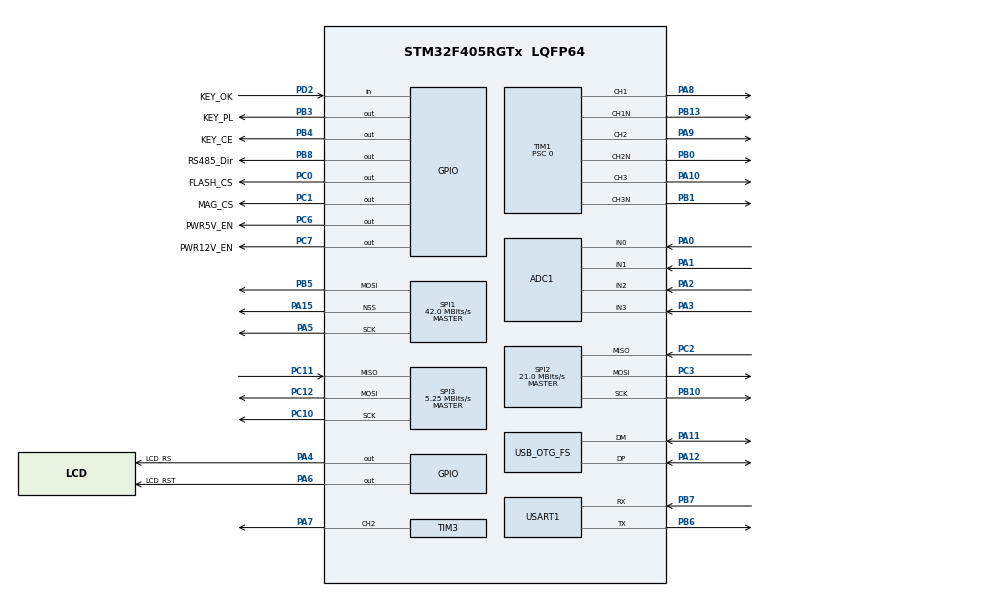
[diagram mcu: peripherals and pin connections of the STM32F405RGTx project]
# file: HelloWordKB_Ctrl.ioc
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ADC1.Channel-0\#ChannelRegularConversion=ADC_CHANNEL_0
ADC1.NbrOfConversionFlag=1
ADC1.Rank-0\#ChannelRegularConversion=1
ADC1.SamplingTime-0\#ChannelRegularConversion=ADC_SAMPLETIME_3CYCLES
ADC1.master=1
Dma.ADC1.3.Direction=DMA_PERIPH_TO_MEMORY
Dma.ADC1.3.FIFOMode=DMA_FIFOMODE_DISABLE
Dma.ADC1.3.Instance=DMA2_Stream0
Dma.ADC1.3.MemDataAlignment=DMA_MDATAALIGN_HALFWORD
Dma.ADC1.3.MemInc=DMA_MINC_ENABLE
Dma.ADC1.3.Mode=DMA_NORMAL
Dma.ADC1.3.PeriphDataAlignment=DMA_PDATAALIGN_HALFWORD
Dma.ADC1.3.PeriphInc=DMA_PINC_DISABLE
Dma.ADC1.3.Priority=DMA_PRIORITY_LOW
Dma.Request0=SPI3_TX
Dma.Request1=USART1_RX
Dma.Request2=USART1_TX
Dma.Request3=ADC1
Dma.Request4=SPI1_TX
Dma.Request5=SPI3_RX
Dma.SPI1_TX.4.Direction=DMA_MEMORY_TO_PERIPH
Dma.SPI1_TX.4.FIFOMode=DMA_FIFOMODE_DISABLE
Dma.SPI1_TX.4.Instance=DMA2_Stream3
Dma.SPI1_TX.4.MemDataAlignment=DMA_MDATAALIGN_BYTE
Dma.SPI1_TX.4.MemInc=DMA_MINC_ENABLE
Dma.SPI1_TX.4.Mode=DMA_NORMAL
Dma.SPI1_TX.4.PeriphDataAlignment=DMA_PDATAALIGN_BYTE
Dma.SPI1_TX.4.PeriphInc=DMA_PINC_DISABLE
Dma.SPI1_TX.4.Priority=DMA_PRIORITY_LOW
Dma.SPI3_RX.5.Direction=DMA_PERIPH_TO_MEMORY
Dma.SPI3_RX.5.FIFOMode=DMA_FIFOMODE_DISABLE
Dma.SPI3_RX.5.Instance=DMA1_Stream0
Dma.SPI3_RX.5.MemDataAlignment=DMA_MDATAALIGN_BYTE
Dma.SPI3_RX.5.MemInc=DMA_MINC_ENABLE
Dma.SPI3_RX.5.Mode=DMA_NORMAL
Dma.SPI3_RX.5.PeriphDataAlignment=DMA_PDATAALIGN_BYTE
Dma.SPI3_RX.5.PeriphInc=DMA_PINC_DISABLE
Dma.SPI3_RX.5.Priority=DMA_PRIORITY_LOW
Dma.SPI3_TX.0.Direction=DMA_MEMORY_TO_PERIPH
Dma.SPI3_TX.0.FIFOMode=DMA_FIFOMODE_DISABLE
Dma.SPI3_TX.0.Instance=DMA1_Stream5
Dma.SPI3_TX.0.MemDataAlignment=DMA_MDATAALIGN_BYTE
Dma.SPI3_TX.0.MemInc=DMA_MINC_ENABLE
Dma.SPI3_TX.0.Mode=DMA_NORMAL
Dma.SPI3_TX.0.PeriphDataAlignment=DMA_PDATAALIGN_BYTE
Dma.SPI3_TX.0.PeriphInc=DMA_PINC_DISABLE
Dma.SPI3_TX.0.Priority=DMA_PRIORITY_LOW
Dma.USART1_RX.1.Direction=DMA_PERIPH_TO_MEMORY
Dma.USART1_RX.1.FIFOMode=DMA_FIFOMODE_DISABLE
Dma.USART1_RX.1.Instance=DMA2_Stream2
Dma.USART1_RX.1.MemDataAlignment=DMA_MDATAALIGN_BYTE
Dma.USART1_RX.1.MemInc=DMA_MINC_ENABLE
Dma.USART1_RX.1.Mode=DMA_NORMAL
Dma.USART1_RX.1.PeriphDataAlignment=DMA_PDATAALIGN_BYTE
Dma.USART1_RX.1.PeriphInc=DMA_PINC_DISABLE
Dma.USART1_RX.1.Priority=DMA_PRIORITY_LOW
Dma.USART1_TX.2.Direction=DMA_MEMORY_TO_PERIPH
Dma.USART1_TX.2.FIFOMode=DMA_FIFOMODE_DISABLE
Dma.USART1_TX.2.Instance=DMA2_Stream7
Dma.USART1_TX.2.MemDataAlignment=DMA_MDATAALIGN_BYTE
Dma.USART1_TX.2.MemInc=DMA_MINC_ENABLE
Dma.USART1_TX.2.Mode=DMA_NORMAL
Dma.USART1_TX.2.PeriphDataAlignment=DMA_PDATAALIGN_BYTE
Dma.USART1_TX.2.PeriphInc=DMA_PINC_DISABLE
Dma.USART1_TX.2.Priority=DMA_PRIORITY_LOW
FREERTOS.Tasks01=defaultTask,24,1024,StartDefaultTask,Default,NULL,Dynamic,NULL,NULL
FREERTOS.configENABLE_FPU=1
FREERTOS.configTOTAL_HEAP_SIZE=65536
Mcu.Family=STM32F4
Mcu.Name=STM32F405RGTx
Mcu.Package=LQFP64
NVIC.DMA1_Stream0_IRQn=true\:5\:0\:false\:false\:true\:true\:false\:true
NVIC.DMA1_Stream5_IRQn=true\:5\:0\:false\:false\:true\:true\:false\:true
NVIC.DMA2_Stream0_IRQn=true\:5\:0\:false\:false\:true\:true\:false\:true
NVIC.DMA2_Stream2_IRQn=true\:5\:0\:false\:false\:true\:true\:false\:true
NVIC.DMA2_Stream3_IRQn=true\:5\:0\:false\:false\:true\:true\:false\:true
NVIC.DMA2_Stream7_IRQn=true\:5\:0\:false\:false\:true\:true\:false\:true
NVIC.OTG_FS_IRQn=true\:5\:0\:false\:false\:true\:true\:false\:true
NVIC.PriorityGroup=NVIC_PRIORITYGROUP_4
PA0-WKUP.Signal=ADCx_IN0
PA1.Signal=ADCx_IN1
PA10.Signal=S_TIM1_CH3
PA11.Mode=Device_Only
PA11.Signal=USB_OTG_FS_DM
PA12.Mode=Device_Only
PA12.Signal=USB_OTG_FS_DP
PA13.Mode=Serial_Wire
PA13.Signal=SYS_JTMS-SWDIO
PA14.Mode=Serial_Wire
PA14.Signal=SYS_JTCK-SWCLK
PA15.Mode=NSS_Signal_Hard_Output
PA15.Signal=SPI1_NSS
PA2.Signal=ADCx_IN2
PA3.Signal=ADCx_IN3
PA4.GPIO_Label=LCD_RS
PA4.Signal=GPIO_Output
PA5.Mode=TX_Only_Simplex_Unidirect_Master
PA5.Signal=SPI1_SCK
PA6.GPIO_Label=LCD_RST
PA6.Signal=GPIO_Output
PA7.Signal=S_TIM3_CH2
PA8.Signal=S_TIM1_CH1
PA9.Signal=S_TIM1_CH2
PB0.Mode=Output Compare2 CH2 CH2N
PB0.Signal=TIM1_CH2N
PB1.Mode=Output Compare3 CH3 CH3N
PB1.Signal=TIM1_CH3N
PB10.Mode=Full_Duplex_Master
PB10.Signal=SPI2_SCK
PB13.Mode=Output Compare1 CH1 CH1N
PB13.Signal=TIM1_CH1N
PB3.GPIO_Label=KEY_PL
PB3.Signal=GPIO_Output
PB4.GPIO_Label=KEY_CE
PB4.Signal=GPIO_Output
PB5.Mode=TX_Only_Simplex_Unidirect_Master
PB5.Signal=SPI1_MOSI
PB6.Mode=Asynchronous
PB6.Signal=USART1_TX
PB7.Mode=Asynchronous
PB7.Signal=USART1_RX
PB8.GPIO_Label=RS485_Dir
PB8.Signal=GPIO_Output
PC0.GPIO_Label=FLASH_CS
PC0.Signal=GPIO_Output
PC1.GPIO_Label=MAG_CS
PC1.Signal=GPIO_Output
PC10.Mode=Full_Duplex_Master
PC10.Signal=SPI3_SCK
PC11.Mode=Full_Duplex_Master
PC11.Signal=SPI3_MISO
PC12.Mode=Full_Duplex_Master
PC12.Signal=SPI3_MOSI
PC2.Mode=Full_Duplex_Master
PC2.Signal=SPI2_MISO
PC3.Mode=Full_Duplex_Master
PC3.Signal=SPI2_MOSI
PC6.GPIO_Label=PWR5V_EN
PC6.Signal=GPIO_Output
PC7.GPIO_Label=PWR12V_EN
PC7.Signal=GPIO_Output
PD2.GPIO_Label=KEY_OK
PD2.Signal=GPIO_Input
PH0-OSC_IN.Mode=HSE-External-Oscillator
PH0-OSC_IN.Signal=RCC_OSC_IN
PH1-OSC_OUT.Mode=HSE-External-Oscillator
PH1-OSC_OUT.Signal=RCC_OSC_OUT
ProjectManager.HeapSize=0x800
ProjectManager.StackSize=0x800
ProjectManager.TargetToolchain=SW4STM32
RCC.48MHZClocksFreq_Value=48000000
RCC.AHBFreq_Value=168000000
RCC.APB1CLKDivider=RCC_HCLK_DIV4
RCC.APB1Freq_Value=42000000
RCC.APB1TimFreq_Value=84000000
RCC.APB2CLKDivider=RCC_HCLK_DIV2
RCC.APB2Freq_Value=84000000
RCC.APB2TimFreq_Value=168000000
RCC.CortexFreq_Value=168000000
RCC.HCLKFreq_Value=168000000
RCC.HSE_VALUE=8000000
RCC.HSI_VALUE=16000000
RCC.LSE_VALUE=32768
RCC.PLLM=4
RCC.PLLN=168
RCC.PLLQ=7
RCC.SYSCLKFreq_VALUE=168000000
RCC.SYSCLKSource=RCC_SYSCLKSOURCE_PLLCLK
RCC.VCOOutputFreq_Value=336000000
SH.ADCx_IN0.0=ADC1_IN0,IN0
SH.ADCx_IN1.0=ADC1_IN1,IN1
SH.ADCx_IN2.0=ADC1_IN2,IN2
SH.ADCx_IN3.0=ADC1_IN3,IN3
SH.S_TIM1_CH1.0=TIM1_CH1,Output Compare1 CH1 CH1N
SH.S_TIM1_CH2.0=TIM1_CH2,Output Compare2 CH2 CH2N
SH.S_TIM1_CH3.0=TIM1_CH3,Output Compare3 CH3 CH3N
SH.S_TIM3_CH2.0=TIM3_CH2,Output Compare2 CH2
SPI1.BaudRatePrescaler=SPI_BAUDRATEPRESCALER_2
SPI1.CalculateBaudRate=42.0 MBits/s
SPI1.Direction=SPI_DIRECTION_2LINES
SPI1.Mode=SPI_MODE_MASTER
SPI1.VirtualNSS=VM_NSSHARD
SPI1.VirtualType=VM_MASTER
SPI2.BaudRatePrescaler=SPI_BAUDRATEPRESCALER_2
SPI2.CalculateBaudRate=21.0 MBits/s
SPI2.Direction=SPI_DIRECTION_2LINES
SPI2.Mode=SPI_MODE_MASTER
SPI2.VirtualType=VM_MASTER
SPI3.BaudRatePrescaler=SPI_BAUDRATEPRESCALER_8
SPI3.CLKPolarity=SPI_POLARITY_HIGH
SPI3.CalculateBaudRate=5.25 MBits/s
SPI3.Direction=SPI_DIRECTION_2LINES
SPI3.Mode=SPI_MODE_MASTER
SPI3.VirtualType=VM_MASTER
TIM1.Channel-Output\ Compare1\ CH1\ CH1N=TIM_CHANNEL_1
TIM1.Channel-Output\ Compare2\ CH2\ CH2N=TIM_CHANNEL_2
TIM1.Channel-Output\ Compare3\ CH3\ CH3N=TIM_CHANNEL_3
TIM1.CounterMode=TIM_COUNTERMODE_CENTERALIGNED1
TIM1.Prescaler=0
TIM3.Channel-Output\ Compare2\ CH2=TIM_CHANNEL_2
USART1.VirtualMode=VM_ASYNC
USB_DEVICE.CLASS_NAME_FS=CUSTOM_HID
USB_DEVICE.MANUFACTURER_STRING-CUSTOM_HID_FS=HelloWord
USB_DEVICE.PRODUCT_STRING_CUSTOMHID_FS=HelloWord KeyBoard-Knob
USB_DEVICE.USBD_CUSTOMHID_OUTREPORT_BUF_SIZE-CUSTOM_HID_FS=64
USB_DEVICE.USBD_CUSTOM_HID_REPORT_DESC_SIZE-CUSTOM_HID_FS=89
USB_DEVICE.VirtualMode-CUSTOM_HID_FS=CustomHid
USB_DEVICE.VirtualModeFS=Custom_Hid_FS
USB_OTG_FS.VirtualMode=Device_Only
VP_FREERTOS_VS_CMSIS_V2.Mode=CMSIS_V2
VP_TIM1_VS_ClockSourceINT.Mode=Internal
VP_TIM1_VS_ClockSourceITR.Mode=TriggerSource_ITR3
VP_TIM3_VS_ClockSourceINT.Mode=Internal
VP_USB_DEVICE_VS_USB_DEVICE_CUSTOM_HID_FS.Mode=CUSTOM_HID_FS
board=custom

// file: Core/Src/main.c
/* USER CODE BEGIN Header */
/**
  ******************************************************************************
  * @file           : main.c
  * @brief          : Main program body
  ******************************************************************************
  * @attention
  *
  * <h2><center>&copy; Copyright (c) 2022 STMicroelectronics.
  * All rights reserved.</center></h2>
  *
  * This software component is licensed by ST under Ultimate Liberty license
  * SLA0044, the "License"; You may not use this file except in compliance with
  * the License. You may obtain a copy of the License at:
  *                             www.st.com/SLA0044
  *
  ******************************************************************************
  */
/* USER CODE END Header */

#include "main.h"
#include "cmsis_os.h"
#include "usb_device.h"
#include <stdio.h>
#include "UserApp.h"

ADC_HandleTypeDef hadc1;
DMA_HandleTypeDef hdma_adc1;

SPI_HandleTypeDef hspi1;
SPI_HandleTypeDef hspi2;
SPI_HandleTypeDef hspi3;
DMA_HandleTypeDef hdma_spi1_tx;
DMA_HandleTypeDef hdma_spi3_tx;
DMA_HandleTypeDef hdma_spi3_rx;

TIM_HandleTypeDef htim1;
TIM_HandleTypeDef htim3;
TIM_HandleTypeDef htim7;

UART_HandleTypeDef huart1;
DMA_HandleTypeDef hdma_usart1_rx;
DMA_HandleTypeDef hdma_usart1_tx;

/* Definitions for defaultTask */
osThreadId_t defaultTaskHandle;
const osThreadAttr_t defaultTask_attributes = {
  .name = "defaultTask",
  .priority = (osPriority_t) osPriorityNormal,
  .stack_size = 1024 * 4
};

void SystemClock_Config(void);
static void MX_GPIO_Init(void);
static void MX_DMA_Init(void);
static void MX_ADC1_Init(void);
static void MX_SPI1_Init(void);
static void MX_SPI2_Init(void);
static void MX_SPI3_Init(void);
static void MX_USART1_UART_Init(void);
static void MX_TIM1_Init(void);
static void MX_TIM3_Init(void);
void StartDefaultTask(void *argument);

int main(void)
{

  /* MCU Configuration--------------------------------------------------------*/

  /* Reset of all peripherals, Initializes the Flash interface and the Systick. */
  HAL_Init();

  /* Configure the system clock */
  SystemClock_Config();

  /* Initialize all configured peripherals */
  MX_GPIO_Init();
  MX_DMA_Init();
  MX_ADC1_Init();
  MX_SPI1_Init();
  MX_SPI2_Init();
  MX_SPI3_Init();
  MX_USART1_UART_Init();
  MX_TIM1_Init();
  MX_TIM3_Init();

  /* Init scheduler */
  osKernelInitialize();

  /* Create the thread(s) */
  /* creation of defaultTask */
  defaultTaskHandle = osThreadNew(StartDefaultTask, NULL, &defaultTask_attributes);

  /* Start scheduler */
  printf("OsKernelStart...\r\n");
  osKernelStart();

  /* We should never get here as control is now taken by the scheduler */
  /* Infinite loop */
  while (1)
  {

  }
}

void SystemClock_Config(void)
{
  RCC_OscInitTypeDef RCC_OscInitStruct = {0};
  RCC_ClkInitTypeDef RCC_ClkInitStruct = {0};

  /** Configure the main internal regulator output voltage
  */
  __HAL_RCC_PWR_CLK_ENABLE();
  __HAL_PWR_VOLTAGESCALING_CONFIG(PWR_REGULATOR_VOLTAGE_SCALE1);
  /** Initializes the CPU, AHB and APB busses clocks
  */
  // Sysclk = 8 / 4 * 144 / 2 = 144MHz
  // HCLK = 144 / 1 = 144MHz
  // APB1 = 144 / 4 = 36MHz(72M for timer): TIM2-5, TIM12-14, USART2-5, SPI2-3
  // APB2 = 144 / 2 = 72MHz(144M for timer): TIM1,8-11, USART1,6, SPI1, ADC1-3
  RCC_OscInitStruct.OscillatorType = RCC_OSCILLATORTYPE_HSE;
  RCC_OscInitStruct.HSEState = RCC_HSE_ON;
  RCC_OscInitStruct.PLL.PLLState = RCC_PLL_ON;
  RCC_OscInitStruct.PLL.PLLSource = RCC_PLLSOURCE_HSE;
  RCC_OscInitStruct.PLL.PLLM = 4;
  RCC_OscInitStruct.PLL.PLLN = 144;
  RCC_OscInitStruct.PLL.PLLP = RCC_PLLP_DIV2;
  RCC_OscInitStruct.PLL.PLLQ = 6;
  if (HAL_RCC_OscConfig(&RCC_OscInitStruct) != HAL_OK)
  {
    Error_Handler();
  }
  /** Initializes the CPU, AHB and APB busses clocks
  */
  RCC_ClkInitStruct.ClockType = RCC_CLOCKTYPE_HCLK|RCC_CLOCKTYPE_SYSCLK
                              |RCC_CLOCKTYPE_PCLK1|RCC_CLOCKTYPE_PCLK2;
  RCC_ClkInitStruct.SYSCLKSource = RCC_SYSCLKSOURCE_PLLCLK;
  RCC_ClkInitStruct.AHBCLKDivider = RCC_SYSCLK_DIV1;
  RCC_ClkInitStruct.APB1CLKDivider = RCC_HCLK_DIV4;
  RCC_ClkInitStruct.APB2CLKDivider = RCC_HCLK_DIV2;

  if (HAL_RCC_ClockConfig(&RCC_ClkInitStruct, FLASH_LATENCY_5) != HAL_OK)
  {
    Error_Handler();
  }
}

static void MX_ADC1_Init(void)
{

  ADC_ChannelConfTypeDef sConfig = {0};

  /** Configure the global features of the ADC (Clock, Resolution, Data Alignment and number of conversion)
  */
  hadc1.Instance = ADC1;
  hadc1.Init.ClockPrescaler = ADC_CLOCK_SYNC_PCLK_DIV4;
  hadc1.Init.Resolution = ADC_RESOLUTION_12B;
  hadc1.Init.ScanConvMode = DISABLE;
  hadc1.Init.ContinuousConvMode = DISABLE;
  hadc1.Init.DiscontinuousConvMode = DISABLE;
  hadc1.Init.ExternalTrigConvEdge = ADC_EXTERNALTRIGCONVEDGE_NONE;
  hadc1.Init.ExternalTrigConv = ADC_SOFTWARE_START;
  hadc1.Init.DataAlign = ADC_DATAALIGN_RIGHT;
  hadc1.Init.NbrOfConversion = 1;
  hadc1.Init.DMAContinuousRequests = DISABLE;
  hadc1.Init.EOCSelection = ADC_EOC_SINGLE_CONV;
  if (HAL_ADC_Init(&hadc1) != HAL_OK)
  {
    Error_Handler();
  }
  /** Configure for the selected ADC regular channel its corresponding rank in the sequencer and its sample time.
  */
  sConfig.Channel = ADC_CHANNEL_0;
  sConfig.Rank = 1;
  sConfig.SamplingTime = ADC_SAMPLETIME_3CYCLES;
  if (HAL_ADC_ConfigChannel(&hadc1, &sConfig) != HAL_OK)
  {
    Error_Handler();
  }

}

static void MX_SPI1_Init(void)
{

  /* SPI1 parameter configuration*/
  // 72MHz / 4 = 18MHz
  hspi1.Instance = SPI1;
  hspi1.Init.Mode = SPI_MODE_MASTER;
  hspi1.Init.Direction = SPI_DIRECTION_2LINES;
  hspi1.Init.DataSize = SPI_DATASIZE_8BIT;
  hspi1.Init.CLKPolarity = SPI_POLARITY_HIGH;
  hspi1.Init.CLKPhase = SPI_PHASE_2EDGE;
  hspi1.Init.NSS = SPI_NSS_SOFT;
  hspi1.Init.BaudRatePrescaler = SPI_BAUDRATEPRESCALER_2;
  hspi1.Init.FirstBit = SPI_FIRSTBIT_MSB;
  hspi1.Init.TIMode = SPI_TIMODE_DISABLE;
  hspi1.Init.CRCCalculation = SPI_CRCCALCULATION_DISABLE;
  hspi1.Init.CRCPolynomial = 10;
  if (HAL_SPI_Init(&hspi1) != HAL_OK)
  {
    Error_Handler();
  }

}

static void MX_SPI2_Init(void)
{

  /* SPI2 parameter configuration*/
  // 36MHz / 4 = 9MHz(111ns)
  hspi2.Instance = SPI2;
  hspi2.Init.Mode = SPI_MODE_MASTER;
  hspi2.Init.Direction = SPI_DIRECTION_2LINES;
  hspi2.Init.DataSize = SPI_DATASIZE_16BIT;
  hspi2.Init.CLKPolarity = SPI_POLARITY_HIGH;
  hspi2.Init.CLKPhase = SPI_PHASE_2EDGE;
  hspi2.Init.NSS = SPI_NSS_SOFT;
  hspi2.Init.BaudRatePrescaler = SPI_BAUDRATEPRESCALER_2;
  hspi2.Init.FirstBit = SPI_FIRSTBIT_MSB;
  hspi2.Init.TIMode = SPI_TIMODE_DISABLE;
  hspi2.Init.CRCCalculation = SPI_CRCCALCULATION_DISABLE;
  hspi2.Init.CRCPolynomial = 10;
  if (HAL_SPI_Init(&hspi2) != HAL_OK)
  {
    Error_Handler();
  }

}

static void MX_SPI3_Init(void)
{

  /* SPI3 parameter configuration*/
  // SPI3 CLK = 36 / 4 = 9MHz(111ns)
  hspi3.Instance = SPI3;
  hspi3.Init.Mode = SPI_MODE_MASTER;
  hspi3.Init.Direction = SPI_DIRECTION_2LINES;
  hspi3.Init.DataSize = SPI_DATASIZE_8BIT;
  hspi3.Init.CLKPolarity = SPI_POLARITY_HIGH;
  hspi3.Init.CLKPhase = SPI_PHASE_1EDGE;
  hspi3.Init.NSS = SPI_NSS_SOFT;
  hspi3.Init.BaudRatePrescaler = SPI_BAUDRATEPRESCALER_4;
  hspi3.Init.FirstBit = SPI_FIRSTBIT_MSB;
  hspi3.Init.TIMode = SPI_TIMODE_DISABLE;
  hspi3.Init.CRCCalculation = SPI_CRCCALCULATION_DISABLE;
  hspi3.Init.CRCPolynomial = 10;
  if (HAL_SPI_Init(&hspi3) != HAL_OK)
  {
    Error_Handler();
  }

}

static void MX_TIM1_Init(void)
{

  TIM_ClockConfigTypeDef sClockSourceConfig = {0};
  TIM_SlaveConfigTypeDef sSlaveConfig = {0};
  TIM_MasterConfigTypeDef sMasterConfig = {0};
  TIM_OC_InitTypeDef sConfigOC = {0};
  TIM_BreakDeadTimeConfigTypeDef sBreakDeadTimeConfig = {0};

  // 144MHz / 3600 = 40KHz
  htim1.Instance = TIM1;
  htim1.Init.Prescaler = 0;
  htim1.Init.CounterMode = TIM_COUNTERMODE_CENTERALIGNED1;
  htim1.Init.Period = 3600 - 1;
  htim1.Init.ClockDivision = TIM_CLOCKDIVISION_DIV1;
  htim1.Init.RepetitionCounter = 0;
  htim1.Init.AutoReloadPreload = TIM_AUTORELOAD_PRELOAD_DISABLE;
  if (HAL_TIM_Base_Init(&htim1) != HAL_OK)
  {
    Error_Handler();
  }
  sClockSourceConfig.ClockSource = TIM_CLOCKSOURCE_INTERNAL;
  if (HAL_TIM_ConfigClockSource(&htim1, &sClockSourceConfig) != HAL_OK)
  {
    Error_Handler();
  }
  if (HAL_TIM_OC_Init(&htim1) != HAL_OK)
  {
    Error_Handler();
  }
  sSlaveConfig.SlaveMode = TIM_SLAVEMODE_DISABLE;
  sSlaveConfig.InputTrigger = TIM_TS_ITR3;
  if (HAL_TIM_SlaveConfigSynchro(&htim1, &sSlaveConfig) != HAL_OK)
  {
    Error_Handler();
  }
  sMasterConfig.MasterOutputTrigger = TIM_TRGO_OC4REF;
  sMasterConfig.MasterSlaveMode = TIM_MASTERSLAVEMODE_DISABLE;
  if (HAL_TIMEx_MasterConfigSynchronization(&htim1, &sMasterConfig) != HAL_OK)
  {
    Error_Handler();
  }
  sConfigOC.OCMode = TIM_OCMODE_PWM1;
  sConfigOC.Pulse = 0;
  sConfigOC.OCPolarity = TIM_OCPOLARITY_HIGH;
  sConfigOC.OCNPolarity = TIM_OCNPOLARITY_HIGH;
  sConfigOC.OCFastMode = TIM_OCFAST_DISABLE;
  sConfigOC.OCIdleState = TIM_OCIDLESTATE_RESET;
  sConfigOC.OCNIdleState = TIM_OCNIDLESTATE_RESET;
  if (HAL_TIM_OC_ConfigChannel(&htim1, &sConfigOC, TIM_CHANNEL_1) != HAL_OK)
  {
    Error_Handler();
  }
  if (HAL_TIM_OC_ConfigChannel(&htim1, &sConfigOC, TIM_CHANNEL_2) != HAL_OK)
  {
    Error_Handler();
  }
  if (HAL_TIM_OC_ConfigChannel(&htim1, &sConfigOC, TIM_CHANNEL_3) != HAL_OK)
  {
    Error_Handler();
  }
  sBreakDeadTimeConfig.OffStateRunMode = TIM_OSSR_DISABLE;
  sBreakDeadTimeConfig.OffStateIDLEMode = TIM_OSSI_DISABLE;
  sBreakDeadTimeConfig.LockLevel = TIM_LOCKLEVEL_OFF;
  sBreakDeadTimeConfig.DeadTime = 0;
  sBreakDeadTimeConfig.BreakState = TIM_BREAK_DISABLE;
  sBreakDeadTimeConfig.BreakPolarity = TIM_BREAKPOLARITY_HIGH;
  sBreakDeadTimeConfig.AutomaticOutput = TIM_AUTOMATICOUTPUT_DISABLE;
  if (HAL_TIMEx_ConfigBreakDeadTime(&htim1, &sBreakDeadTimeConfig) != HAL_OK)
  {
    Error_Handler();
  }
  HAL_TIM_MspPostInit(&htim1);

}

static void MX_TIM3_Init(void)
{

  TIM_ClockConfigTypeDef sClockSourceConfig = {0};
  TIM_MasterConfigTypeDef sMasterConfig = {0};
  TIM_OC_InitTypeDef sConfigOC = {0};

  // 72MHz / 720 = 100KHz
  // 100KHz / 100 = 1KHz
  htim3.Instance = TIM3;
  htim3.Init.Prescaler = (720-1);
  htim3.Init.CounterMode = TIM_COUNTERMODE_UP;
  htim3.Init.Period = (100-1);
  htim3.Init.ClockDivision = TIM_CLOCKDIVISION_DIV1;
  htim3.Init.AutoReloadPreload = TIM_AUTORELOAD_PRELOAD_DISABLE;
  if (HAL_TIM_Base_Init(&htim3) != HAL_OK)
  {
    Error_Handler();
  }
  sClockSourceConfig.ClockSource = TIM_CLOCKSOURCE_INTERNAL;
  if (HAL_TIM_ConfigClockSource(&htim3, &sClockSourceConfig) != HAL_OK)
  {
    Error_Handler();
  }
  if (HAL_TIM_OC_Init(&htim3) != HAL_OK)
  {
    Error_Handler();
  }
  sMasterConfig.MasterOutputTrigger = TIM_TRGO_RESET;
  sMasterConfig.MasterSlaveMode = TIM_MASTERSLAVEMODE_DISABLE;
  if (HAL_TIMEx_MasterConfigSynchronization(&htim3, &sMasterConfig) != HAL_OK)
  {
    Error_Handler();
  }
  sConfigOC.OCMode = TIM_OCMODE_PWM1;
  sConfigOC.Pulse = 95;
  sConfigOC.OCPolarity = TIM_OCPOLARITY_HIGH;
  sConfigOC.OCFastMode = TIM_OCFAST_DISABLE;
  if (HAL_TIM_OC_ConfigChannel(&htim3, &sConfigOC, TIM_CHANNEL_2) != HAL_OK)
  {
    Error_Handler();
  }
  HAL_TIM_MspPostInit(&htim3);

}

static void MX_USART1_UART_Init(void)
{

  huart1.Instance = USART1;
  huart1.Init.BaudRate = 115200;
  huart1.Init.WordLength = UART_WORDLENGTH_8B;
  huart1.Init.StopBits = UART_STOPBITS_1;
  huart1.Init.Parity = UART_PARITY_NONE;
  huart1.Init.Mode = UART_MODE_TX_RX;
  huart1.Init.HwFlowCtl = UART_HWCONTROL_NONE;
  huart1.Init.OverSampling = UART_OVERSAMPLING_16;
  if (HAL_UART_Init(&huart1) != HAL_OK)
  {
    Error_Handler();
  }

}

static void MX_DMA_Init(void)
{

  /* DMA controller clock enable */
  __HAL_RCC_DMA1_CLK_ENABLE();
  __HAL_RCC_DMA2_CLK_ENABLE();

  /* DMA interrupt init */
  /* DMA1_Stream0_IRQn interrupt configuration */
  HAL_NVIC_SetPriority(DMA1_Stream0_IRQn, 5, 0);
  HAL_NVIC_EnableIRQ(DMA1_Stream0_IRQn);
  /* DMA1_Stream5_IRQn interrupt configuration */
  HAL_NVIC_SetPriority(DMA1_Stream5_IRQn, 5, 0);
  HAL_NVIC_EnableIRQ(DMA1_Stream5_IRQn);
  /* DMA2_Stream0_IRQn interrupt configuration */
  HAL_NVIC_SetPriority(DMA2_Stream0_IRQn, 5, 0);
  HAL_NVIC_EnableIRQ(DMA2_Stream0_IRQn);
  /* DMA2_Stream2_IRQn interrupt configuration */
  HAL_NVIC_SetPriority(DMA2_Stream2_IRQn, 5, 0);
  HAL_NVIC_EnableIRQ(DMA2_Stream2_IRQn);
  /* DMA2_Stream3_IRQn interrupt configuration */
  HAL_NVIC_SetPriority(DMA2_Stream3_IRQn, 5, 0);
  HAL_NVIC_EnableIRQ(DMA2_Stream3_IRQn);
  /* DMA2_Stream7_IRQn interrupt configuration */
  HAL_NVIC_SetPriority(DMA2_Stream7_IRQn, 5, 0);
  HAL_NVIC_EnableIRQ(DMA2_Stream7_IRQn);

}

static void MX_GPIO_Init(void)
{
  GPIO_InitTypeDef GPIO_InitStruct = {0};

  /* GPIO Ports Clock Enable */
  __HAL_RCC_GPIOH_CLK_ENABLE();
  __HAL_RCC_GPIOC_CLK_ENABLE();
  __HAL_RCC_GPIOA_CLK_ENABLE();
  __HAL_RCC_GPIOB_CLK_ENABLE();
  __HAL_RCC_GPIOD_CLK_ENABLE();

  /*Configure GPIO pin Output Level */
  HAL_GPIO_WritePin(GPIOC, FLASH_CS_Pin|MAG_CS_Pin|PWR5V_EN_Pin|PWR12V_EN_Pin, GPIO_PIN_RESET);

  /*Configure GPIO pin Output Level */
  HAL_GPIO_WritePin(GPIOA, LCD_RS_Pin|LCD_RST_Pin, GPIO_PIN_RESET);

  /*Configure GPIO pin Output Level */
  HAL_GPIO_WritePin(GPIOB, KEY_PL_Pin|KEY_CE_Pin|RS485_Dir_Pin, GPIO_PIN_RESET);

  /*Configure GPIO pins : FLASH_CS_Pin MAG_CS_Pin PWR5V_EN_Pin PWR12V_EN_Pin */
  GPIO_InitStruct.Pin = FLASH_CS_Pin|MAG_CS_Pin|PWR5V_EN_Pin|PWR12V_EN_Pin;
  GPIO_InitStruct.Mode = GPIO_MODE_OUTPUT_PP;
  GPIO_InitStruct.Pull = GPIO_NOPULL;
  GPIO_InitStruct.Speed = GPIO_SPEED_FREQ_LOW;
  HAL_GPIO_Init(GPIOC, &GPIO_InitStruct);

  /*Configure GPIO pins : LCD_RS_Pin LCD_RST_Pin */
  GPIO_InitStruct.Pin = LCD_RS_Pin|LCD_RST_Pin|LCD_CS_Pin;
  GPIO_InitStruct.Mode = GPIO_MODE_OUTPUT_PP;
  GPIO_InitStruct.Pull = GPIO_NOPULL;
  GPIO_InitStruct.Speed = GPIO_SPEED_FREQ_LOW;
  HAL_GPIO_Init(GPIOA, &GPIO_InitStruct);

  /*Configure GPIO pin : KEY_OK_Pin */
  GPIO_InitStruct.Pin = KEY_OK_Pin;
  GPIO_InitStruct.Mode = GPIO_MODE_INPUT;
  GPIO_InitStruct.Pull = GPIO_NOPULL;
  HAL_GPIO_Init(KEY_OK_GPIO_Port, &GPIO_InitStruct);

  /*Configure GPIO pins : KEY_PL_Pin KEY_CE_Pin RS485_Dir_Pin */
  GPIO_InitStruct.Pin = KEY_PL_Pin|KEY_CE_Pin|RS485_Dir_Pin;
  GPIO_InitStruct.Mode = GPIO_MODE_OUTPUT_PP;
  GPIO_InitStruct.Pull = GPIO_NOPULL;
  GPIO_InitStruct.Speed = GPIO_SPEED_FREQ_LOW;
  HAL_GPIO_Init(GPIOB, &GPIO_InitStruct);

    HAL_GPIO_WritePin(GPIOC, FLASH_CS_Pin|MAG_CS_Pin, GPIO_PIN_SET);
    HAL_GPIO_WritePin(LCD_CS_GPIO_Port, LCD_CS_Pin, GPIO_PIN_SET);
}

void StartDefaultTask(void *argument)
{
  /* init code for USB_DEVICE */
  MX_USB_DEVICE_Init();
  /* USER CODE BEGIN 5 */
    UserMain();

  /* Infinite loop */
  for(;;)
  {
    osDelay(10);
  }
  /* USER CODE END 5 */
}

extern void OnTimerCallback(TIM_TypeDef *timInstance);
void HAL_TIM_PeriodElapsedCallback(TIM_HandleTypeDef *htim)
{
    if (htim->Instance == TIM6) {
        HAL_IncTick();
    }
        /* USER CODE BEGIN Callback 1 */
    else
    {
        OnTimerCallback(htim->Instance);
    }
    /* USER CODE END Callback 1 */
}

void Error_Handler(void)
{
}

/************************ (C) COPYRIGHT STMicroelectronics *****END OF FILE****/
